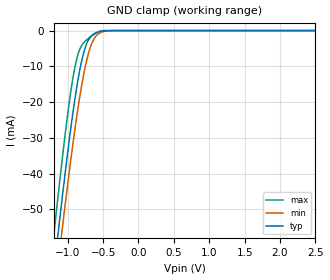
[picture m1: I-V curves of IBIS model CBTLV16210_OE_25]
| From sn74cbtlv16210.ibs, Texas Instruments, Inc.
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[Model]   CBTLV16210_OE_25
Model_type  Input
Vinl = 0.7
Vinh = 1.7
| variable   typ   min   max
C_comp   2.41pF   1.83pF   2.89pF
[Temperature Range]   40   100   -40
| Ambient temperature   25   85   -40
[Voltage range]   2.5   2.3   2.7
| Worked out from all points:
|   GND clamp passes 1 mA (typ) near -0.63 V on its own axis
[GND Clamp]
| CBTLV16210_OE_25
|   Voltage   I(typ)   I(min)   I(max)
-2.5V     -322.5mA   -324.4mA   -322.1mA
-1.205V   -69.14mA   -77.55mA   -58.97mA
-1.185V   -65.56mA   -74.04mA   -55.26mA
-1.135V   -56.72mA   -65.38mA   -46.15mA
-1.085V   -48.1mA    -56.91mA   -37.34mA
-960mV    -27.97mA   -36.8mA    -17.62mA
-870mV    -15.62mA   -23.79mA   -7.765mA
-755mV    -4.939mA   -10.4mA    -2.998mA
-690mV    -2.132mA   -5.286mA   -1.919mA
-620mV    -811.1uA   -2.078mA   -945.3uA
-370mV    -2.165uA   -34.13uA   -40.97nA
2.5V      1.122nA    59.66nA    7.278pA
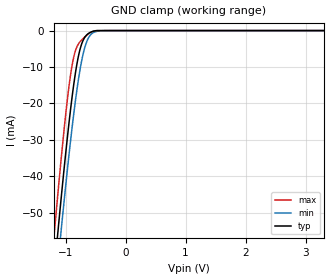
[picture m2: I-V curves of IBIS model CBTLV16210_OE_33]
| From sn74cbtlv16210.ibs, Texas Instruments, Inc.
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[Model]   CBTLV16210_OE_33
Model_type  Input
Vinl = 0.8
Vinh = 2.0
| variable   typ   min   max
C_comp   2.45pF   1.81pF   2.93pF
[Temperature Range]   40   100   -40
| Ambient temperature   25   85   -40
[Voltage range]   3.3   3   3.6
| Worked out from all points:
|   GND clamp passes 1 mA (typ) near -0.63 V on its own axis
[GND Clamp]
| CBTLV16210_OE_33
|   Voltage   I(typ)   I(min)   I(max)
-3.3V     -485.3mA   -483.2mA   -490.7mA
-1.19V    -66.45mA   -74.91mA   -56.19mA
-1.125V   -54.98mA   -63.67mA   -44.36mA
-1.085V   -48.1mA    -56.91mA   -37.34mA
-1.07V    -45.57mA   -54.41mA   -34.77mA
-955mV    -27.22mA   -36.03mA   -16.95mA
-865mV    -15.02mA   -23.12mA   -7.389mA
-745mV    -4.366mA   -9.479mA   -2.808mA
-670mV    -1.628mA   -4.136mA   -1.625mA
-590mV    -511.7uA   -1.312mA   -609.3uA
-355mV    -1.584uA   -26.33uA   -23.28nA
3.3V      1.127nA    59.66nA    9.713pA
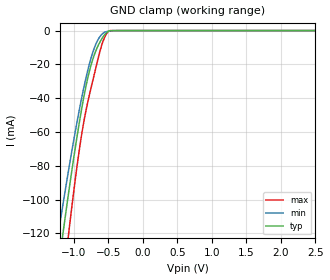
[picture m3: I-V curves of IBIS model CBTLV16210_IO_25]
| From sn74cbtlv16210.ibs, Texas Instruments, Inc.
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[Model]   CBTLV16210_IO_25
Model_type  Terminator
| variable   typ   min   max
C_comp   4.52pF   3.96pF   4.95pF
| C_tri-state   4.52pF   3.96pF   4.95pF
[Temperature Range]   40   100   -40
| Ambient temperature   25   85   -40
[Voltage range]   2.5   2.3   2.7
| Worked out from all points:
|   GND clamp passes 1 mA (typ) near -0.52 V on its own axis
[GND Clamp]
| CBTLV16210_IO_25
|   Voltage   I(typ)   I(min)   I(max)
-2.5V     -573.9mA   -491mA     -699.6mA
-1.245V   -146.2mA   -125.1mA   -181.3mA
-1.215V   -136.9mA   -117.2mA   -170.1mA
-1.16V    -120.3mA   -103.1mA   -149.8mA
-1.075V   -95.4mA    -81.92mA   -119.5mA
-915mV    -52.7mA    -45.41mA   -68.59mA
-855mV    -38.97mA   -33.39mA   -53.6mA
-800mV    -28.14mA   -23.58mA   -42.41mA
-685mV    -12.22mA   -8.272mA   -22.49mA
-565mV    -2.972mA   -1.214mA   -4.893mA
-475mV    -54.48uA   -286.4uA   -34.04uA
2.5V      1.214nA    60.76nA    11.78pA
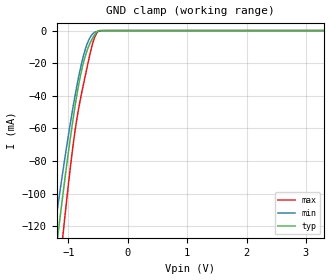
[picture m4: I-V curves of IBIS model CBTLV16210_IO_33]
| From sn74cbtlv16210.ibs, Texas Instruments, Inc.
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[Model]   CBTLV16210_IO_33
Model_type  Terminator
| variable   typ   min   max
C_comp   4.32pF   3.75pF   4.86pF
| C_tri-state   4.32pF   3.75pF   4.86pF
[Temperature Range]   40   100   -40
| Ambient temperature   25   85   -40
[Voltage range]   3.3   3   3.6
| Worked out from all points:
|   GND clamp passes 1 mA (typ) near -0.52 V on its own axis
[GND Clamp]
| CBTLV16210_IO_33
|   Voltage   I(typ)   I(min)   I(max)
-3.3V     -863.3mA   -739.1mA   -1.049A
-1.26V    -150.8mA   -129.1mA   -187mA
-1.23V    -141.5mA   -121.2mA   -175.7mA
-1.17V    -123.3mA   -105.6mA   -153.4mA
-1.09V    -99.71mA   -85.58mA   -124.7mA
-920mV    -53.92mA   -46.46mA   -69.97mA
-805mV    -29.05mA   -24.41mA   -43.35mA
-675mV    -11.22mA   -7.34mA    -20.78mA
-610mV    -5.804mA   -2.863mA   -10.35mA
-550mV    -2.196mA   -897.2uA   -3.496mA
-475mV    -54.48uA   -286.4uA   -34.04uA
3.3V      1.257nA    61.35nA    15.91pA
